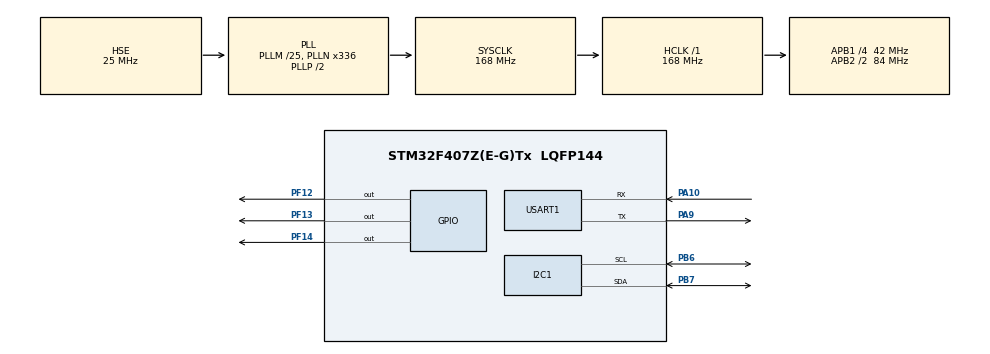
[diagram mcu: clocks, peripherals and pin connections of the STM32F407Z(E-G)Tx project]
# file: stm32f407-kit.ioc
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Dma.Request0=USART1_RX
Dma.USART1_RX.0.Direction=DMA_PERIPH_TO_MEMORY
Dma.USART1_RX.0.FIFOMode=DMA_FIFOMODE_DISABLE
Dma.USART1_RX.0.Instance=DMA2_Stream2
Dma.USART1_RX.0.MemDataAlignment=DMA_MDATAALIGN_BYTE
Dma.USART1_RX.0.MemInc=DMA_MINC_ENABLE
Dma.USART1_RX.0.Mode=DMA_CIRCULAR
Dma.USART1_RX.0.PeriphDataAlignment=DMA_PDATAALIGN_BYTE
Dma.USART1_RX.0.PeriphInc=DMA_PINC_DISABLE
Dma.USART1_RX.0.Priority=DMA_PRIORITY_LOW
I2C1.I2C_Mode=I2C_Fast
Mcu.Family=STM32F4
Mcu.Name=STM32F407Z(E-G)Tx
Mcu.Package=LQFP144
NVIC.PriorityGroup=NVIC_PRIORITYGROUP_4
PA10.Mode=Asynchronous
PA10.Signal=USART1_RX
PA13.Mode=Serial_Wire
PA13.Signal=SYS_JTMS-SWDIO
PA14.Mode=Serial_Wire
PA14.Signal=SYS_JTCK-SWCLK
PA9.Mode=Asynchronous
PA9.Signal=USART1_TX
PB6.Mode=I2C
PB6.Signal=I2C1_SCL
PB7.Mode=I2C
PB7.Signal=I2C1_SDA
PC14-OSC32_IN.Mode=LSE-External-Oscillator
PC14-OSC32_IN.Signal=RCC_OSC32_IN
PC15-OSC32_OUT.Mode=LSE-External-Oscillator
PC15-OSC32_OUT.Signal=RCC_OSC32_OUT
PF12.PinState=GPIO_PIN_SET
PF12.Signal=GPIO_Output
PF13.PinState=GPIO_PIN_SET
PF13.Signal=GPIO_Output
PF14.PinState=GPIO_PIN_SET
PF14.Signal=GPIO_Output
PH0-OSC_IN.Mode=HSE-External-Oscillator
PH0-OSC_IN.Signal=RCC_OSC_IN
PH1-OSC_OUT.Mode=HSE-External-Oscillator
PH1-OSC_OUT.Signal=RCC_OSC_OUT
ProjectManager.HeapSize=0x200
ProjectManager.StackSize=0x400
ProjectManager.TargetToolchain=CMake
RCC.48MHZClocksFreq_Value=84000000
RCC.AHBFreq_Value=168000000
RCC.APB1CLKDivider=RCC_HCLK_DIV4
RCC.APB1Freq_Value=42000000
RCC.APB1TimFreq_Value=84000000
RCC.APB2CLKDivider=RCC_HCLK_DIV2
RCC.APB2Freq_Value=84000000
RCC.APB2TimFreq_Value=168000000
RCC.CortexFreq_Value=168000000
RCC.HCLKFreq_Value=168000000
RCC.HSE_VALUE=25000000
RCC.HSI_VALUE=16000000
RCC.PLLM=25
RCC.PLLN=336
RCC.PLLSourceVirtual=RCC_PLLSOURCE_HSE
RCC.SYSCLKFreq_VALUE=168000000
RCC.SYSCLKSource=RCC_SYSCLKSOURCE_PLLCLK
RCC.VCOOutputFreq_Value=336000000
USART1.VirtualMode=VM_ASYNC
board=custom

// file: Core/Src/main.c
/* USER CODE BEGIN Header */
/**
  ******************************************************************************
  * @file           : main.c
  * @brief          : Main program body
  ******************************************************************************
  * @attention
  *
  * Copyright (c) 2025 STMicroelectronics.
  * All rights reserved.
  *
  * This software is licensed under terms that can be found in the LICENSE file
  * in the root directory of this software component.
  * If no LICENSE file comes with this software, it is provided AS-IS.
  *
  ******************************************************************************
  */
/* USER CODE END Header */
#include "main.h"

/* USER CODE BEGIN Includes */
#include "ap.h"
/* USER CODE END Includes */

I2C_HandleTypeDef hi2c1;

UART_HandleTypeDef huart1;
DMA_HandleTypeDef hdma_usart1_rx;

void SystemClock_Config(void);
static void MX_GPIO_Init(void);
static void MX_DMA_Init(void);
static void MX_USART1_UART_Init(void);
static void MX_I2C1_Init(void);

int main(void)
{

  /* MCU Configuration--------------------------------------------------------*/

  /* Reset of all peripherals, Initializes the Flash interface and the Systick. */
  HAL_Init();

  /* Configure the system clock */
  SystemClock_Config();

  /* Initialize all configured peripherals */
  MX_GPIO_Init();
  MX_DMA_Init();
  MX_USART1_UART_Init();
  MX_I2C1_Init();
  /* USER CODE BEGIN 2 */

  hwInit();
  apInit();
  apMain();

  /* USER CODE END 2 */

  /* Infinite loop */
  while (1)
  {

  }
}

void SystemClock_Config(void)
{
  RCC_OscInitTypeDef RCC_OscInitStruct = {0};
  RCC_ClkInitTypeDef RCC_ClkInitStruct = {0};

  /** Configure the main internal regulator output voltage
  */
  __HAL_RCC_PWR_CLK_ENABLE();
  __HAL_PWR_VOLTAGESCALING_CONFIG(PWR_REGULATOR_VOLTAGE_SCALE1);

  /** Initializes the RCC Oscillators according to the specified parameters
  * in the RCC_OscInitTypeDef structure.
  */
  RCC_OscInitStruct.OscillatorType = RCC_OSCILLATORTYPE_HSE;
  RCC_OscInitStruct.HSEState = RCC_HSE_ON;
  RCC_OscInitStruct.PLL.PLLState = RCC_PLL_ON;
  RCC_OscInitStruct.PLL.PLLSource = RCC_PLLSOURCE_HSE;
  RCC_OscInitStruct.PLL.PLLM = 25;
  RCC_OscInitStruct.PLL.PLLN = 336;
  RCC_OscInitStruct.PLL.PLLP = RCC_PLLP_DIV2;
  RCC_OscInitStruct.PLL.PLLQ = 4;
  if (HAL_RCC_OscConfig(&RCC_OscInitStruct) != HAL_OK)
  {
    Error_Handler();
  }

  /** Initializes the CPU, AHB and APB buses clocks
  */
  RCC_ClkInitStruct.ClockType = RCC_CLOCKTYPE_HCLK|RCC_CLOCKTYPE_SYSCLK
                              |RCC_CLOCKTYPE_PCLK1|RCC_CLOCKTYPE_PCLK2;
  RCC_ClkInitStruct.SYSCLKSource = RCC_SYSCLKSOURCE_PLLCLK;
  RCC_ClkInitStruct.AHBCLKDivider = RCC_SYSCLK_DIV1;
  RCC_ClkInitStruct.APB1CLKDivider = RCC_HCLK_DIV4;
  RCC_ClkInitStruct.APB2CLKDivider = RCC_HCLK_DIV2;

  if (HAL_RCC_ClockConfig(&RCC_ClkInitStruct, FLASH_LATENCY_5) != HAL_OK)
  {
    Error_Handler();
  }
}

static void MX_I2C1_Init(void)
{

  hi2c1.Instance = I2C1;
  hi2c1.Init.ClockSpeed = 400000;
  hi2c1.Init.DutyCycle = I2C_DUTYCYCLE_2;
  hi2c1.Init.OwnAddress1 = 0;
  hi2c1.Init.AddressingMode = I2C_ADDRESSINGMODE_7BIT;
  hi2c1.Init.DualAddressMode = I2C_DUALADDRESS_DISABLE;
  hi2c1.Init.OwnAddress2 = 0;
  hi2c1.Init.GeneralCallMode = I2C_GENERALCALL_DISABLE;
  hi2c1.Init.NoStretchMode = I2C_NOSTRETCH_DISABLE;
  if (HAL_I2C_Init(&hi2c1) != HAL_OK)
  {
    Error_Handler();
  }

}

static void MX_USART1_UART_Init(void)
{

  huart1.Instance = USART1;
  huart1.Init.BaudRate = 115200;
  huart1.Init.WordLength = UART_WORDLENGTH_8B;
  huart1.Init.StopBits = UART_STOPBITS_1;
  huart1.Init.Parity = UART_PARITY_NONE;
  huart1.Init.Mode = UART_MODE_TX_RX;
  huart1.Init.HwFlowCtl = UART_HWCONTROL_NONE;
  huart1.Init.OverSampling = UART_OVERSAMPLING_16;
  if (HAL_UART_Init(&huart1) != HAL_OK)
  {
    Error_Handler();
  }

}

static void MX_DMA_Init(void)
{

  /* DMA controller clock enable */
  __HAL_RCC_DMA2_CLK_ENABLE();

}

static void MX_GPIO_Init(void)
{
  GPIO_InitTypeDef GPIO_InitStruct = {0};

  /* GPIO Ports Clock Enable */
  __HAL_RCC_GPIOC_CLK_ENABLE();
  __HAL_RCC_GPIOH_CLK_ENABLE();
  __HAL_RCC_GPIOF_CLK_ENABLE();
  __HAL_RCC_GPIOG_CLK_ENABLE();
  __HAL_RCC_GPIOA_CLK_ENABLE();
  __HAL_RCC_GPIOB_CLK_ENABLE();

  /*Configure GPIO pin Output Level */
  HAL_GPIO_WritePin(GPIOF, GPIO_PIN_12|GPIO_PIN_13|GPIO_PIN_14, GPIO_PIN_SET);

  /*Configure GPIO pins : PF12 PF13 PF14 */
  GPIO_InitStruct.Pin = GPIO_PIN_12|GPIO_PIN_13|GPIO_PIN_14;
  GPIO_InitStruct.Mode = GPIO_MODE_OUTPUT_PP;
  GPIO_InitStruct.Pull = GPIO_NOPULL;
  GPIO_InitStruct.Speed = GPIO_SPEED_FREQ_LOW;
  HAL_GPIO_Init(GPIOF, &GPIO_InitStruct);

  /*Configure GPIO pins : PG2 PG3 PG4 PG5 */
  GPIO_InitStruct.Pin = GPIO_PIN_2|GPIO_PIN_3|GPIO_PIN_4|GPIO_PIN_5;
  GPIO_InitStruct.Mode = GPIO_MODE_INPUT;
  GPIO_InitStruct.Pull = GPIO_PULLUP;
  HAL_GPIO_Init(GPIOG, &GPIO_InitStruct);

}

void Error_Handler(void)
{
  __disable_irq();
  while (1)
  {
  }
}
